###############################################################################
# SiliconForge 7nm Standard Cell LEF
# Process: 7nm FinFET, 9-metal, 0.70V
# Row height: 0.270µm (6 M1 pitches)
# Site width: 0.054µm (1 CPP)
###############################################################################

VERSION 5.8 ;
BUSBITCHARS "[]" ;
DIVIDERCHAR "/" ;

UNITS
  DATABASE MICRONS 1000 ;
END UNITS

###############################################################################
# MANUFACTURING GRID
###############################################################################
MANUFACTURINGGRID 0.001 ;

###############################################################################
# TECHNOLOGY LAYERS
###############################################################################

LAYER poly
  TYPE MASTERSLICE ;
END poly

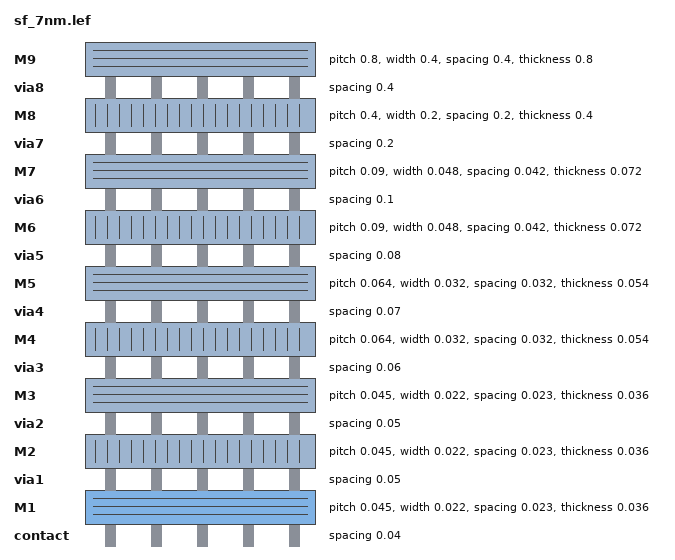
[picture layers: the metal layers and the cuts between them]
LAYER contact
  TYPE CUT ;
  SPACING 0.040 ;
END contact

LAYER M1
  TYPE ROUTING ;
  DIRECTION HORIZONTAL ;
  PITCH 0.045 ;
  WIDTH 0.022 ;
  SPACING 0.023 ;
  OFFSET 0.0225 ;
  RESISTANCE RPERSQ 12.8 ;
  CAPACITANCE CPERSQDIST 0.000115 ;
  THICKNESS 0.036 ;
  HEIGHT 0.000 ;
  AREA 0.0010 ;
END M1

LAYER via1
  TYPE CUT ;
  SPACING 0.050 ;
END via1

LAYER M2
  TYPE ROUTING ;
  DIRECTION VERTICAL ;
  PITCH 0.045 ;
  WIDTH 0.022 ;
  SPACING 0.023 ;
  OFFSET 0.0225 ;
  RESISTANCE RPERSQ 12.8 ;
  CAPACITANCE CPERSQDIST 0.000110 ;
  THICKNESS 0.036 ;
  HEIGHT 0.036 ;
END M2

LAYER via2
  TYPE CUT ;
  SPACING 0.050 ;
END via2

LAYER M3
  TYPE ROUTING ;
  DIRECTION HORIZONTAL ;
  PITCH 0.045 ;
  WIDTH 0.022 ;
  SPACING 0.023 ;
  OFFSET 0.0225 ;
  RESISTANCE RPERSQ 12.0 ;
  CAPACITANCE CPERSQDIST 0.000105 ;
  THICKNESS 0.036 ;
  HEIGHT 0.072 ;
END M3

LAYER via3
  TYPE CUT ;
  SPACING 0.060 ;
END via3

LAYER M4
  TYPE ROUTING ;
  DIRECTION VERTICAL ;
  PITCH 0.064 ;
  WIDTH 0.032 ;
  SPACING 0.032 ;
  OFFSET 0.032 ;
  RESISTANCE RPERSQ 6.4 ;
  CAPACITANCE CPERSQDIST 0.000098 ;
  THICKNESS 0.054 ;
  HEIGHT 0.108 ;
END M4

LAYER via4
  TYPE CUT ;
  SPACING 0.070 ;
END via4

LAYER M5
  TYPE ROUTING ;
  DIRECTION HORIZONTAL ;
  PITCH 0.064 ;
  WIDTH 0.032 ;
  SPACING 0.032 ;
  OFFSET 0.032 ;
  RESISTANCE RPERSQ 6.4 ;
  CAPACITANCE CPERSQDIST 0.000092 ;
  THICKNESS 0.054 ;
  HEIGHT 0.162 ;
END M5

LAYER via5
  TYPE CUT ;
  SPACING 0.080 ;
END via5

LAYER M6
  TYPE ROUTING ;
  DIRECTION VERTICAL ;
  PITCH 0.090 ;
  WIDTH 0.048 ;
  SPACING 0.042 ;
  OFFSET 0.045 ;
  RESISTANCE RPERSQ 3.2 ;
  CAPACITANCE CPERSQDIST 0.000085 ;
  THICKNESS 0.072 ;
  HEIGHT 0.216 ;
END M6

LAYER via6
  TYPE CUT ;
  SPACING 0.100 ;
END via6

LAYER M7
  TYPE ROUTING ;
  DIRECTION HORIZONTAL ;
  PITCH 0.090 ;
  WIDTH 0.048 ;
  SPACING 0.042 ;
  OFFSET 0.045 ;
  RESISTANCE RPERSQ 3.2 ;
  CAPACITANCE CPERSQDIST 0.000078 ;
  THICKNESS 0.072 ;
  HEIGHT 0.288 ;
END M7

LAYER via7
  TYPE CUT ;
  SPACING 0.200 ;
END via7

LAYER M8
  TYPE ROUTING ;
  DIRECTION VERTICAL ;
  PITCH 0.400 ;
  WIDTH 0.200 ;
  SPACING 0.200 ;
  OFFSET 0.200 ;
  RESISTANCE RPERSQ 0.5 ;
  CAPACITANCE CPERSQDIST 0.000060 ;
  THICKNESS 0.400 ;
  HEIGHT 0.360 ;
END M8

LAYER via8
  TYPE CUT ;
  SPACING 0.400 ;
END via8

LAYER M9
  TYPE ROUTING ;
  DIRECTION HORIZONTAL ;
  PITCH 0.800 ;
  WIDTH 0.400 ;
  SPACING 0.400 ;
  OFFSET 0.400 ;
  RESISTANCE RPERSQ 0.2 ;
  CAPACITANCE CPERSQDIST 0.000045 ;
  THICKNESS 0.800 ;
  HEIGHT 0.760 ;
END M9

###############################################################################
# VIA DEFINITIONS
###############################################################################

VIA VIA12 DEFAULT
  LAYER M1 ;
    RECT -0.011 -0.011 0.011 0.011 ;
  LAYER via1 ;
    RECT -0.011 -0.011 0.011 0.011 ;
  LAYER M2 ;
    RECT -0.011 -0.011 0.011 0.011 ;
END VIA12

VIA VIA23 DEFAULT
  LAYER M2 ;
    RECT -0.011 -0.011 0.011 0.011 ;
  LAYER via2 ;
    RECT -0.011 -0.011 0.011 0.011 ;
  LAYER M3 ;
    RECT -0.011 -0.011 0.011 0.011 ;
END VIA23

###############################################################################
# SITE DEFINITION
###############################################################################

SITE CoreSite
  CLASS CORE ;
  SYMMETRY Y ;
  SIZE 0.054 BY 0.270 ;
END CoreSite

###############################################################################
# MACRO DEFINITIONS
###############################################################################

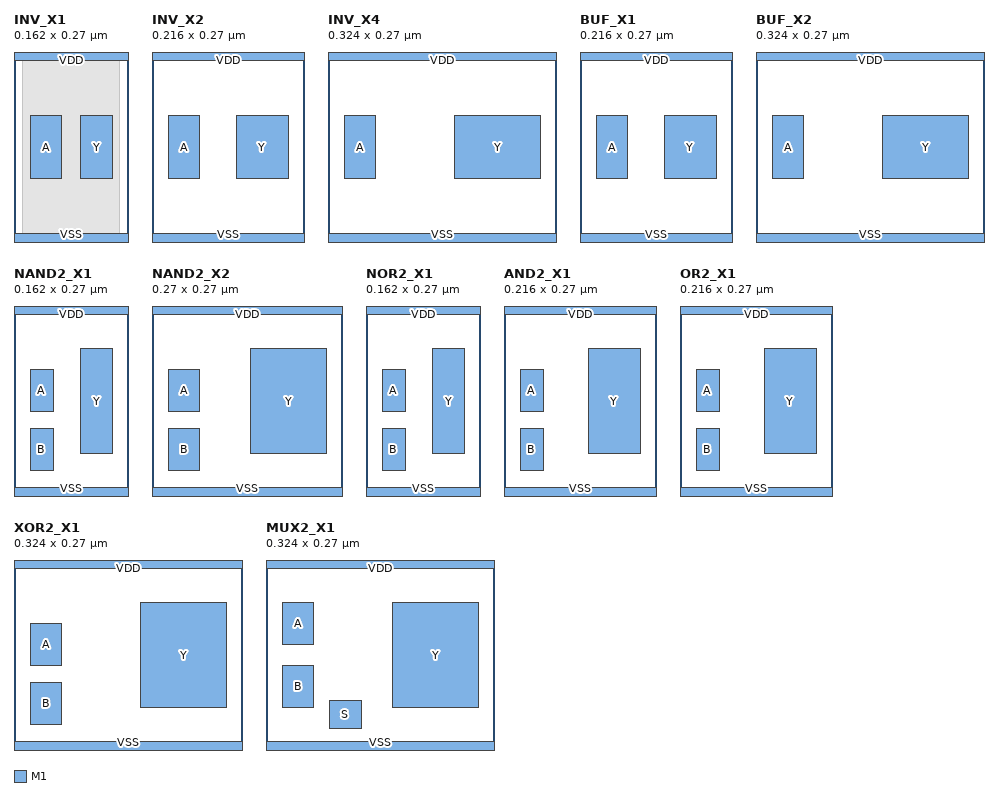
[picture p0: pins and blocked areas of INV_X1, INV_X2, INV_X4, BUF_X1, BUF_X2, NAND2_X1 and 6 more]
MACRO INV_X1
  CLASS CORE ;
  ORIGIN 0 0 ;
  SIZE 0.162 BY 0.270 ;
  SYMMETRY X Y ;
  SITE CoreSite ;
  PIN A
    DIRECTION INPUT ;
    PORT
      LAYER M1 ;
        RECT 0.023 0.090 0.068 0.180 ;
    END
  END A
  PIN Y
    DIRECTION OUTPUT ;
    PORT
      LAYER M1 ;
        RECT 0.095 0.090 0.140 0.180 ;
    END
  END Y
  PIN VDD
    DIRECTION INOUT ;
    USE POWER ;
    PORT
      LAYER M1 ;
        RECT 0.000 0.258 0.162 0.270 ;
    END
  END VDD
  PIN VSS
    DIRECTION INOUT ;
    USE GROUND ;
    PORT
      LAYER M1 ;
        RECT 0.000 0.000 0.162 0.012 ;
    END
  END VSS
  OBS
    LAYER M1 ;
      RECT 0.012 0.012 0.150 0.258 ;
  END
END INV_X1

MACRO INV_X2
  CLASS CORE ;
  ORIGIN 0 0 ;
  SIZE 0.216 BY 0.270 ;
  SYMMETRY X Y ;
  SITE CoreSite ;
  PIN A
    DIRECTION INPUT ;
    PORT LAYER M1 ; RECT 0.023 0.090 0.068 0.180 ; END
  END A
  PIN Y
    DIRECTION OUTPUT ;
    PORT LAYER M1 ; RECT 0.120 0.090 0.194 0.180 ; END
  END Y
  PIN VDD DIRECTION INOUT ; USE POWER ;
    PORT LAYER M1 ; RECT 0.000 0.258 0.216 0.270 ; END
  END VDD
  PIN VSS DIRECTION INOUT ; USE GROUND ;
    PORT LAYER M1 ; RECT 0.000 0.000 0.216 0.012 ; END
  END VSS
END INV_X2

MACRO INV_X4
  CLASS CORE ;
  SIZE 0.324 BY 0.270 ;
  SYMMETRY X Y ; SITE CoreSite ;
  PIN A DIRECTION INPUT ; PORT LAYER M1 ; RECT 0.023 0.090 0.068 0.180 ; END END A
  PIN Y DIRECTION OUTPUT ; PORT LAYER M1 ; RECT 0.180 0.090 0.302 0.180 ; END END Y
  PIN VDD DIRECTION INOUT ; USE POWER ; PORT LAYER M1 ; RECT 0.000 0.258 0.324 0.270 ; END END VDD
  PIN VSS DIRECTION INOUT ; USE GROUND ; PORT LAYER M1 ; RECT 0.000 0.000 0.324 0.012 ; END END VSS
END INV_X4

MACRO BUF_X1
  CLASS CORE ;
  SIZE 0.216 BY 0.270 ;
  SYMMETRY X Y ; SITE CoreSite ;
  PIN A DIRECTION INPUT ; PORT LAYER M1 ; RECT 0.023 0.090 0.068 0.180 ; END END A
  PIN Y DIRECTION OUTPUT ; PORT LAYER M1 ; RECT 0.120 0.090 0.194 0.180 ; END END Y
  PIN VDD DIRECTION INOUT ; USE POWER ; PORT LAYER M1 ; RECT 0.000 0.258 0.216 0.270 ; END END VDD
  PIN VSS DIRECTION INOUT ; USE GROUND ; PORT LAYER M1 ; RECT 0.000 0.000 0.216 0.012 ; END END VSS
END BUF_X1

MACRO BUF_X2
  CLASS CORE ;
  SIZE 0.324 BY 0.270 ;
  SYMMETRY X Y ; SITE CoreSite ;
  PIN A DIRECTION INPUT ; PORT LAYER M1 ; RECT 0.023 0.090 0.068 0.180 ; END END A
  PIN Y DIRECTION OUTPUT ; PORT LAYER M1 ; RECT 0.180 0.090 0.302 0.180 ; END END Y
  PIN VDD DIRECTION INOUT ; USE POWER ; PORT LAYER M1 ; RECT 0.000 0.258 0.324 0.270 ; END END VDD
  PIN VSS DIRECTION INOUT ; USE GROUND ; PORT LAYER M1 ; RECT 0.000 0.000 0.324 0.012 ; END END VSS
END BUF_X2

MACRO NAND2_X1
  CLASS CORE ;
  SIZE 0.162 BY 0.270 ;
  SYMMETRY X Y ; SITE CoreSite ;
  PIN A DIRECTION INPUT ; PORT LAYER M1 ; RECT 0.023 0.120 0.056 0.180 ; END END A
  PIN B DIRECTION INPUT ; PORT LAYER M1 ; RECT 0.023 0.036 0.056 0.096 ; END END B
  PIN Y DIRECTION OUTPUT ; PORT LAYER M1 ; RECT 0.095 0.060 0.140 0.210 ; END END Y
  PIN VDD DIRECTION INOUT ; USE POWER ; PORT LAYER M1 ; RECT 0.000 0.258 0.162 0.270 ; END END VDD
  PIN VSS DIRECTION INOUT ; USE GROUND ; PORT LAYER M1 ; RECT 0.000 0.000 0.162 0.012 ; END END VSS
END NAND2_X1

MACRO NAND2_X2
  CLASS CORE ;
  SIZE 0.270 BY 0.270 ;
  SYMMETRY X Y ; SITE CoreSite ;
  PIN A DIRECTION INPUT ; PORT LAYER M1 ; RECT 0.023 0.120 0.068 0.180 ; END END A
  PIN B DIRECTION INPUT ; PORT LAYER M1 ; RECT 0.023 0.036 0.068 0.096 ; END END B
  PIN Y DIRECTION OUTPUT ; PORT LAYER M1 ; RECT 0.140 0.060 0.248 0.210 ; END END Y
  PIN VDD DIRECTION INOUT ; USE POWER ; PORT LAYER M1 ; RECT 0.000 0.258 0.270 0.270 ; END END VDD
  PIN VSS DIRECTION INOUT ; USE GROUND ; PORT LAYER M1 ; RECT 0.000 0.000 0.270 0.012 ; END END VSS
END NAND2_X2

MACRO NOR2_X1
  CLASS CORE ;
  SIZE 0.162 BY 0.270 ;
  SYMMETRY X Y ; SITE CoreSite ;
  PIN A DIRECTION INPUT ; PORT LAYER M1 ; RECT 0.023 0.120 0.056 0.180 ; END END A
  PIN B DIRECTION INPUT ; PORT LAYER M1 ; RECT 0.023 0.036 0.056 0.096 ; END END B
  PIN Y DIRECTION OUTPUT ; PORT LAYER M1 ; RECT 0.095 0.060 0.140 0.210 ; END END Y
  PIN VDD DIRECTION INOUT ; USE POWER ; PORT LAYER M1 ; RECT 0.000 0.258 0.162 0.270 ; END END VDD
  PIN VSS DIRECTION INOUT ; USE GROUND ; PORT LAYER M1 ; RECT 0.000 0.000 0.162 0.012 ; END END VSS
END NOR2_X1

MACRO AND2_X1
  CLASS CORE ;
  SIZE 0.216 BY 0.270 ;
  SYMMETRY X Y ; SITE CoreSite ;
  PIN A DIRECTION INPUT ; PORT LAYER M1 ; RECT 0.023 0.120 0.056 0.180 ; END END A
  PIN B DIRECTION INPUT ; PORT LAYER M1 ; RECT 0.023 0.036 0.056 0.096 ; END END B
  PIN Y DIRECTION OUTPUT ; PORT LAYER M1 ; RECT 0.120 0.060 0.194 0.210 ; END END Y
  PIN VDD DIRECTION INOUT ; USE POWER ; PORT LAYER M1 ; RECT 0.000 0.258 0.216 0.270 ; END END VDD
  PIN VSS DIRECTION INOUT ; USE GROUND ; PORT LAYER M1 ; RECT 0.000 0.000 0.216 0.012 ; END END VSS
END AND2_X1

MACRO OR2_X1
  CLASS CORE ;
  SIZE 0.216 BY 0.270 ;
  SYMMETRY X Y ; SITE CoreSite ;
  PIN A DIRECTION INPUT ; PORT LAYER M1 ; RECT 0.023 0.120 0.056 0.180 ; END END A
  PIN B DIRECTION INPUT ; PORT LAYER M1 ; RECT 0.023 0.036 0.056 0.096 ; END END B
  PIN Y DIRECTION OUTPUT ; PORT LAYER M1 ; RECT 0.120 0.060 0.194 0.210 ; END END Y
  PIN VDD DIRECTION INOUT ; USE POWER ; PORT LAYER M1 ; RECT 0.000 0.258 0.216 0.270 ; END END VDD
  PIN VSS DIRECTION INOUT ; USE GROUND ; PORT LAYER M1 ; RECT 0.000 0.000 0.216 0.012 ; END END VSS
END OR2_X1

MACRO XOR2_X1
  CLASS CORE ;
  SIZE 0.324 BY 0.270 ;
  SYMMETRY X Y ; SITE CoreSite ;
  PIN A DIRECTION INPUT ; PORT LAYER M1 ; RECT 0.023 0.120 0.068 0.180 ; END END A
  PIN B DIRECTION INPUT ; PORT LAYER M1 ; RECT 0.023 0.036 0.068 0.096 ; END END B
  PIN Y DIRECTION OUTPUT ; PORT LAYER M1 ; RECT 0.180 0.060 0.302 0.210 ; END END Y
  PIN VDD DIRECTION INOUT ; USE POWER ; PORT LAYER M1 ; RECT 0.000 0.258 0.324 0.270 ; END END VDD
  PIN VSS DIRECTION INOUT ; USE GROUND ; PORT LAYER M1 ; RECT 0.000 0.000 0.324 0.012 ; END END VSS
END XOR2_X1

MACRO MUX2_X1
  CLASS CORE ;
  SIZE 0.324 BY 0.270 ;
  SYMMETRY X Y ; SITE CoreSite ;
  PIN A DIRECTION INPUT ; PORT LAYER M1 ; RECT 0.023 0.150 0.068 0.210 ; END END A
  PIN B DIRECTION INPUT ; PORT LAYER M1 ; RECT 0.023 0.060 0.068 0.120 ; END END B
  PIN S DIRECTION INPUT ; PORT LAYER M1 ; RECT 0.090 0.030 0.135 0.070 ; END END S
  PIN Y DIRECTION OUTPUT ; PORT LAYER M1 ; RECT 0.180 0.060 0.302 0.210 ; END END Y
  PIN VDD DIRECTION INOUT ; USE POWER ; PORT LAYER M1 ; RECT 0.000 0.258 0.324 0.270 ; END END VDD
  PIN VSS DIRECTION INOUT ; USE GROUND ; PORT LAYER M1 ; RECT 0.000 0.000 0.324 0.012 ; END END VSS
END MUX2_X1

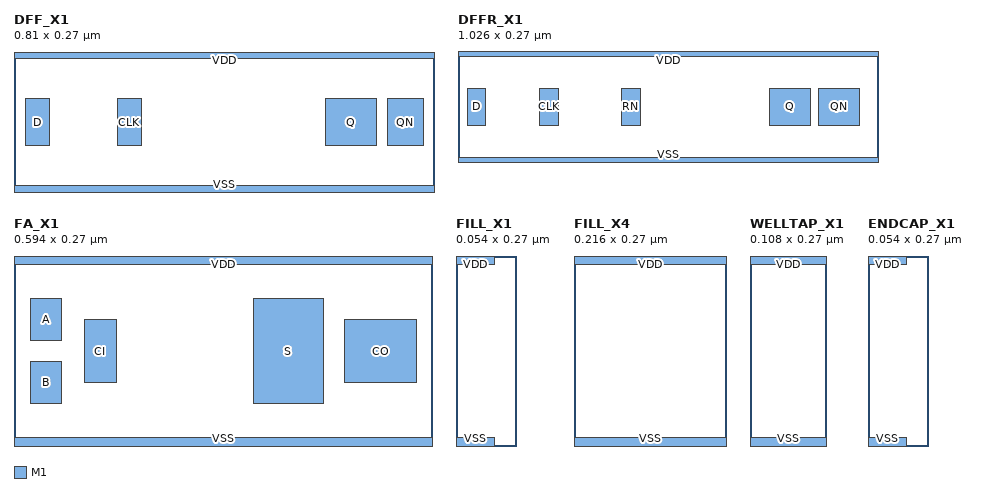
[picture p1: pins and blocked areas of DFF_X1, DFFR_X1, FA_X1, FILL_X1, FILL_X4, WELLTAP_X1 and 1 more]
MACRO DFF_X1
  CLASS CORE ;
  SIZE 0.810 BY 0.270 ;
  SYMMETRY X Y ; SITE CoreSite ;
  PIN D DIRECTION INPUT ; PORT LAYER M1 ; RECT 0.023 0.090 0.068 0.180 ; END END D
  PIN CLK DIRECTION INPUT ; PORT LAYER M1 ; RECT 0.200 0.090 0.245 0.180 ; END END CLK
  PIN Q DIRECTION OUTPUT ; PORT LAYER M1 ; RECT 0.600 0.090 0.700 0.180 ; END END Q
  PIN QN DIRECTION OUTPUT ; PORT LAYER M1 ; RECT 0.720 0.090 0.790 0.180 ; END END QN
  PIN VDD DIRECTION INOUT ; USE POWER ; PORT LAYER M1 ; RECT 0.000 0.258 0.810 0.270 ; END END VDD
  PIN VSS DIRECTION INOUT ; USE GROUND ; PORT LAYER M1 ; RECT 0.000 0.000 0.810 0.012 ; END END VSS
END DFF_X1

MACRO DFFR_X1
  CLASS CORE ;
  SIZE 1.026 BY 0.270 ;
  SYMMETRY X Y ; SITE CoreSite ;
  PIN D DIRECTION INPUT ; PORT LAYER M1 ; RECT 0.023 0.090 0.068 0.180 ; END END D
  PIN CLK DIRECTION INPUT ; PORT LAYER M1 ; RECT 0.200 0.090 0.245 0.180 ; END END CLK
  PIN RN DIRECTION INPUT ; PORT LAYER M1 ; RECT 0.400 0.090 0.445 0.180 ; END END RN
  PIN Q DIRECTION OUTPUT ; PORT LAYER M1 ; RECT 0.760 0.090 0.860 0.180 ; END END Q
  PIN QN DIRECTION OUTPUT ; PORT LAYER M1 ; RECT 0.880 0.090 0.980 0.180 ; END END QN
  PIN VDD DIRECTION INOUT ; USE POWER ; PORT LAYER M1 ; RECT 0.000 0.258 1.026 0.270 ; END END VDD
  PIN VSS DIRECTION INOUT ; USE GROUND ; PORT LAYER M1 ; RECT 0.000 0.000 1.026 0.012 ; END END VSS
END DFFR_X1

MACRO FA_X1
  CLASS CORE ;
  SIZE 0.594 BY 0.270 ;
  SYMMETRY X Y ; SITE CoreSite ;
  PIN A DIRECTION INPUT ; PORT LAYER M1 ; RECT 0.023 0.150 0.068 0.210 ; END END A
  PIN B DIRECTION INPUT ; PORT LAYER M1 ; RECT 0.023 0.060 0.068 0.120 ; END END B
  PIN CI DIRECTION INPUT ; PORT LAYER M1 ; RECT 0.100 0.090 0.145 0.180 ; END END CI
  PIN S DIRECTION OUTPUT ; PORT LAYER M1 ; RECT 0.340 0.060 0.440 0.210 ; END END S
  PIN CO DIRECTION OUTPUT ; PORT LAYER M1 ; RECT 0.470 0.090 0.572 0.180 ; END END CO
  PIN VDD DIRECTION INOUT ; USE POWER ; PORT LAYER M1 ; RECT 0.000 0.258 0.594 0.270 ; END END VDD
  PIN VSS DIRECTION INOUT ; USE GROUND ; PORT LAYER M1 ; RECT 0.000 0.000 0.594 0.012 ; END END VSS
END FA_X1

MACRO FILL_X1
  CLASS CORE SPACER ;
  SIZE 0.054 BY 0.270 ;
  SYMMETRY X Y ; SITE CoreSite ;
  PIN VDD DIRECTION INOUT ; USE POWER ; PORT LAYER M1 ; RECT 0.000 0.258 0.054 0.270 ; END END VDD
  PIN VSS DIRECTION INOUT ; USE GROUND ; PORT LAYER M1 ; RECT 0.000 0.000 0.054 0.012 ; END END VSS
END FILL_X1

MACRO FILL_X4
  CLASS CORE SPACER ;
  SIZE 0.216 BY 0.270 ;
  SYMMETRY X Y ; SITE CoreSite ;
  PIN VDD DIRECTION INOUT ; USE POWER ; PORT LAYER M1 ; RECT 0.000 0.258 0.216 0.270 ; END END VDD
  PIN VSS DIRECTION INOUT ; USE GROUND ; PORT LAYER M1 ; RECT 0.000 0.000 0.216 0.012 ; END END VSS
END FILL_X4

MACRO WELLTAP_X1
  CLASS CORE WELLTAP ;
  SIZE 0.108 BY 0.270 ;
  SYMMETRY X Y ; SITE CoreSite ;
  PIN VDD DIRECTION INOUT ; USE POWER ; PORT LAYER M1 ; RECT 0.000 0.258 0.108 0.270 ; END END VDD
  PIN VSS DIRECTION INOUT ; USE GROUND ; PORT LAYER M1 ; RECT 0.000 0.000 0.108 0.012 ; END END VSS
END WELLTAP_X1

MACRO ENDCAP_X1
  CLASS CORE ENDCAP ;
  SIZE 0.054 BY 0.270 ;
  SYMMETRY X Y ; SITE CoreSite ;
  PIN VDD DIRECTION INOUT ; USE POWER ; PORT LAYER M1 ; RECT 0.000 0.258 0.054 0.270 ; END END VDD
  PIN VSS DIRECTION INOUT ; USE GROUND ; PORT LAYER M1 ; RECT 0.000 0.000 0.054 0.012 ; END END VSS
END ENDCAP_X1

END LIBRARY
